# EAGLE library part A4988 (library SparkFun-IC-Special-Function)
DMOS Microstepping Driver with Translator(IC-11483)

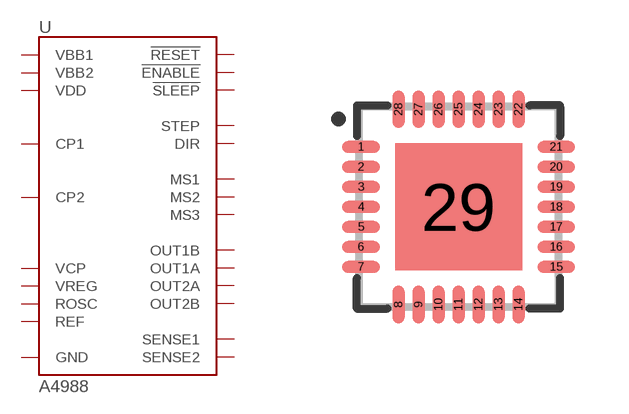
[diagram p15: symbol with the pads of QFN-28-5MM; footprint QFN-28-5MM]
Designator prefix U

## A4988ALT1 (PROD_ID: IC-11483)  [QFN-28-5MM]
1  OUT2B
2  !ENABLE!  in
3  GND  pwr
4  CP1
5  CP2
6  VCP
8  VREG
9  MS1  in
10  MS2  in
11  MS3  in
12  !RESET!  in
13  ROSC
14  !SLEEP!  in
15  VDD  pwr
16  STEP  in
17  REF
18  GND  pwr
19  DIR  in
21  OUT1B
22  VBB1
23  SENSE1
24  OUT1A
26  OUT2A
27  SENSE2
28  VBB2
29  GND  pwr

## Footprint QFN-28-5MM (pad centres in mm)
smd 0.94 x 0.3: 1 -2.44,1.5; 2 -2.44,1; 3 -2.44,0.5; 4 -2.44,0; 5 -2.44,-0.5; 6 -2.44,-1; 7 -2.44,-1.5; 15 2.44,-1.5; 16 2.44,-1; 17 2.44,-0.5; 18 2.44,0; 19 2.44,0.5; 20 2.44,1; 21 2.44,1.5
smd 0.3 x 0.94: 8 -1.5,-2.44; 9 -1,-2.44; 10 -0.5,-2.44; 11 0,-2.44; 12 0.5,-2.44; 13 1,-2.44; 14 1.5,-2.44; 22 1.5,2.44; 23 1,2.44; 24 0.5,2.44; 25 0,2.44; 26 -0.5,2.44; 27 -1,2.44; 28 -1.5,2.44
smd 3.175 x 3.175: 29 0,0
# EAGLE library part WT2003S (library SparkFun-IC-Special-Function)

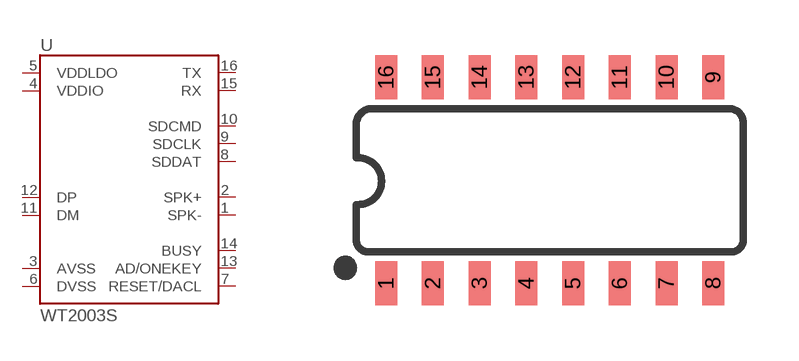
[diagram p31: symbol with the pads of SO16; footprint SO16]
Designator prefix U

## WT2003SS (PROD_ID: IC-14204)  [SO16]
1  SPK-
2  SPK+
3  AVSS
4  VDDIO
5  VDDLDO
6  DVSS
7  RESET/DACL
8  SDDAT
9  SDCLK
10  SDCMD
11  DM
12  DP
13  AD/ONEKEY
14  BUSY
15  RX
16  TX

## WT2003SH4  [SO16]
1  SDCMD
2  SDDAT
3  SDCLK
4  DM
5  DP
6  RX
7  AD/ONEKEY
8  AVSS
9  RESET/DACL
10  VDDIO
11  VDDLDO
12  DVSS
13  SPK-
14  SPK+
15  BUSY
16  TX

## Footprint SO16 (pad centres in mm)
SOIC, 0.15 inch width
smd 0.6 x 1.2: 1 -4.445,-2.8; 2 -3.175,-2.8; 3 -1.905,-2.8; 4 -0.635,-2.8; 5 0.635,-2.8; 6 1.905,-2.8; 7 3.175,-2.8; 8 4.445,-2.8; 9 4.445,2.8; 10 3.175,2.8; 11 1.905,2.8; 12 0.635,2.8; 13 -0.635,2.8; 14 -1.905,2.8; 15 -3.175,2.8; 16 -4.445,2.8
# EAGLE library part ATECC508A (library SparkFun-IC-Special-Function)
ATECC508A CryptoAuthentication Device Cryptographic Co-processor with Secure Hardware-Based Key Storage ECDSA: FIPS186-3 Elliptic Curve Digital Signature Algorithm ECDH: FIPS SP800-56A Elliptic Curve Diffie-Hellman Algorithm NIST Standard P256 Elliptic Curve Support SHA-256 Hash Algorithm with HMAC Option 1 MHz Standard I2C Interface 2.0V to 5.5V Supply Voltage Range 1.8V to 5.5V IO levels Datasheet SparkFun Products SparkFun Cryptographic Co-Processor Breakout ATECC508A Qwiic (DEV-15573)

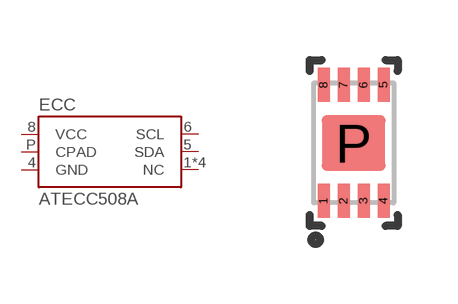
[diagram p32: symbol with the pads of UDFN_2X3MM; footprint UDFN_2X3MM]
Designator prefix ECC

## ATECC508AUDFN_2X3MM (PROD_ID: IC-14661)  [UDFN_2X3MM]
1  NC  nc
2  NC  nc
3  NC  nc
4  GND  pwr
5  SDA
6  SCL
7  NC  nc
8  VCC  pwr
P  CPAD  pwr

## Footprint UDFN_2X3MM (pad centres in mm)
smd 0.3 x 0.85: 1 -0.75,-1.45; 2 -0.25,-1.45; 3 0.25,-1.45; 4 0.75,-1.45; 5 0.75,1.45; 6 0.25,1.45; 7 -0.25,1.45; 8 -0.75,1.45
smd 1.6 x 1.4: P 0,0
